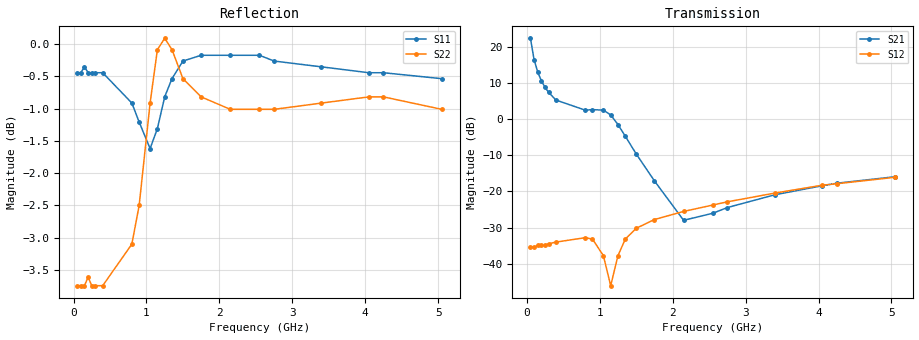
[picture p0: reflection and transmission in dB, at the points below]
!AT-36408
!S-PARAMETERS at Vce=6.0 V  Ic=100 mA.  LAST UPDATED 08-05-96
# ghz s ma r 50
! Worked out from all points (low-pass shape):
!   101 points, 50 MHz to 5.05 GHz, reference 50 ohm
!   highest |S21| = 22.29 dB at 50 MHz (marker M1); lowest = -28.0 dB at 2.15 GHz (marker M2)
!   |S21| within 3 dB of the highest: start of sweep to 75.42 MHz
!   lowest |S11| = -1.6 dB at 1.05 GHz (marker M3), VSWR 10.76, Z = 4.67 + j3.47 ohm
!   |S11| at or under -10 dB: nowhere
!   |S22| runs from -3.7 to 0.1 dB; largest |S21 - S12| = 13
!   S11 on the Smith chart (normalised r, x): 50 MHz: 0.03, -0.07; 800 MHz: 0.05, +0.09; 2.75 GHz: 0.02, +0.26; 4.05 GHz: 0.03, +0.44; 5.05 GHz: 0.04, +0.66
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0.05  0.95 -172.0  13.02 94.0  0.017 10.0  0.65 -165.0
0.1  0.95 -177.0  6.6 88.0  0.017 10.0  0.65 -171.0
0.15  0.96 -179.0  4.44 84.0  0.018 11.0  0.65 -173.0
0.2  0.95 179.0  3.37 80.0  0.018 12.0  0.66 -174.0
0.25  0.95 178.0  2.74 77.0  0.018 14.0  0.65 -174.0
0.3  0.95 177.0  2.33 74.0  0.019 15.0  0.65 -173.0
0.4  0.95 176.0  1.83 67.0  0.02 18.0  0.65 -172.0
0.8  0.9 170.0  1.33 33.0  0.023 9.0  0.7 -163.0
0.9  0.87 169.0  1.35 18.0  0.022 -1.0  0.75 -159.0
1.05  0.83 172.0  1.33 -14.0  0.013 -37.0  0.9 -159.0
1.15  0.86 174.0  1.14 -41.0  0.005 -133.0  0.99 -164.0
1.25  0.91 174.0  0.84 -65.0  0.013 140.0  1.01 -170.0
1.35  0.94 173.0  0.58 -82.0  0.022 117.0  0.99 -174.0
1.5  0.97 169.0  0.33 -101.0  0.031 101.0  0.94 -176.0
1.75  0.98 165.0  0.14 -125.0  0.041 90.0  0.91 -177.0
2.15  0.98 159.0  0.04 175.0  0.053 82.0  0.89 -178.0
2.55  0.98 154.0  0.05 104.0  0.065 78.0  0.89 -178.0
2.75  0.97 151.0  0.06 92.0  0.072 76.0  0.89 -178.0
3.4  0.96 142.0  0.09 73.0  0.095 70.0  0.9 -180.0
4.05  0.95 132.0  0.12 63.0  0.122 61.0  0.91 177.0
4.25  0.95 129.0  0.13 60.0  0.128 59.0  0.91 175.0
5.05  0.94 113.0  0.16 47.0  0.157 48.0  0.89 169.0
